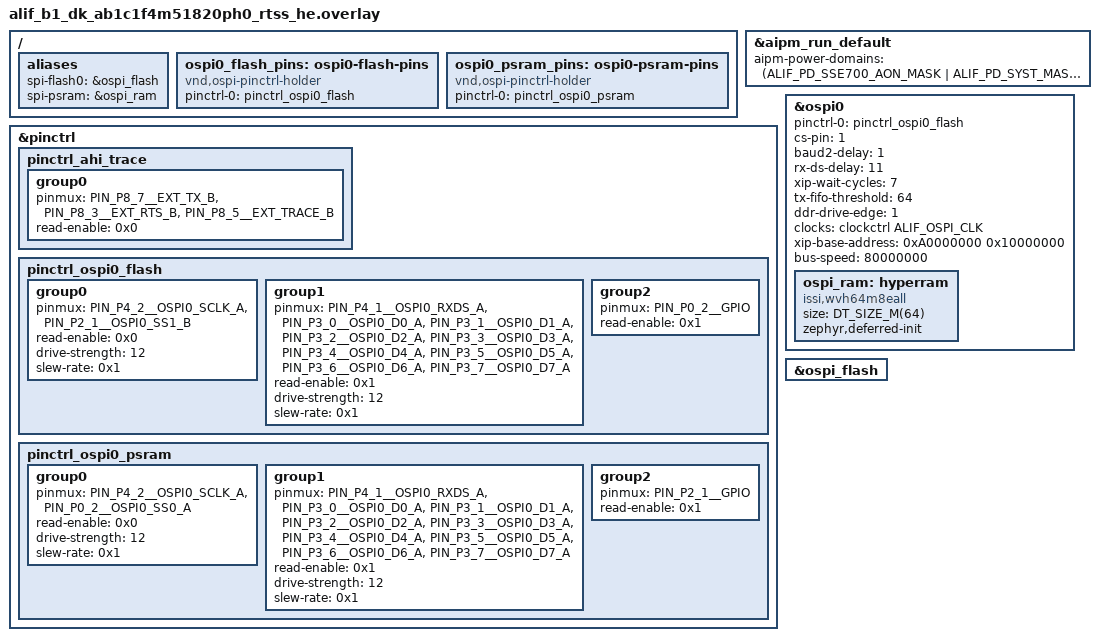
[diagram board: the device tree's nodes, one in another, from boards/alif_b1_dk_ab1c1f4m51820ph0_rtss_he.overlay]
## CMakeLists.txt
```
# SPDX-License-Identifier: Apache-2.0

cmake_minimum_required(VERSION 3.20.0)
find_package(Zephyr REQUIRED HINTS $ENV{ZEPHYR_BASE})
project(spi_flash)

target_sources(app PRIVATE src/main.c)
target_sources_ifdef(CONFIG_MEMC app PRIVATE src/flash_to_psram.c)
```

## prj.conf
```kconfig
# Copyright (C) 2026 Alif Semiconductor.
# SPDX-License-Identifier: Apache-2.0

#FLASH
CONFIG_STDOUT_CONSOLE=y
CONFIG_FLASH=y
CONFIG_LOG=y
CONFIG_EVENTS=y
CONFIG_MAIN_STACK_SIZE=8192
CONFIG_FLASH_LOG_LEVEL_DBG=n

# CRC32 used by flash_to_psram_verify()
CONFIG_CRC=y

# Bring-up diagnostics: flush prints synchronously and dump faults.
CONFIG_LOG_MODE_IMMEDIATE=y
CONFIG_EXCEPTION_STACK_TRACE=y

#RAM
CONFIG_PRINTK=y
CONFIG_ARM_MPU=y
CONFIG_MEMC=y
CONFIG_MEMC_OSPI_ALIF=y
CONFIG_USE_ALIF_HAL_OSPI=y
```

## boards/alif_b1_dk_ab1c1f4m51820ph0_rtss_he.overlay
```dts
/*
 * SPDX-FileCopyrightText: Copyright Alif Semiconductor
 * SPDX-License-Identifier: Apache-2.0
 */

#include <dt-bindings/misc/alif_aipm_common.h>

/* Keep the Debug Subsystem (DBSS) powered so a debugger stays connected. */
&aipm_run_default {
	aipm-power-domains = <(ALIF_PD_SSE700_AON_MASK |
			       ALIF_PD_SYST_MASK | ALIF_PD_SESS_MASK |
			       ALIF_PD_DBSS_MASK)>;
};

/*
 * Combined OSPI0 configuration: both the external OSPI flash (SS1_B / P2_1)
 * and the HyperRAM PSRAM (SS0_A / P0_2) share the single OSPI0 controller,
 * the SCLK, the D0..D7 data lines and the RXDS strobe.
 *
 * Build this WITHOUT the `ospi-flash` / `ospi-psram` snippets -- this overlay
 * already declares both devices and all pinctrl states.
 *
 * KEY: the two devices must NOT be muxed onto the bus at the same time. When
 * the PSRAM chip-select (SS0_A) is muxed while the flash performs an octal-DDR
 * read, the physically-present HyperRAM loads the shared RXDS strobe and the
 * read never completes (hang). The loader (flash_to_psram.c) therefore owns
 * two pinctrl states and swaps them every chunk so that exactly one device is
 * connected to the bus at a time; the deselected device's chip-select is
 * parked on GPIO (released) so it stays fully quiescent.
 *
 * The PSRAM (memc) driver is `zephyr,deferred-init`: it never runs. The loader
 * drives the OSPI0 HAL directly to alternate flash reads and PSRAM XiP writes.
 */

/ {
	aliases {
		spi-flash0 = &ospi_flash;
		spi-psram = &ospi_ram;
	};

	/*
	 * Helper nodes that let the loader apply either pin state at run time.
	 * They carry no `reg` (the Alif pinctrl driver ignores it) and a
	 * placeholder compatible (`vnd,ospi-pinctrl-holder`, no driver) so that
	 * gen_defines types `pinctrl-0` as phandles and PINCTRL_DT_DEFINE() in
	 * the loader can own a pinctrl_dev_config for each state. Keeping the
	 * custom "psram" state off &ospi0 avoids breaking the flash driver's
	 * PINCTRL_DT_DEFINE.
	 */
	ospi0_flash_pins: ospi0-flash-pins {
		compatible = "vnd,ospi-pinctrl-holder";
		pinctrl-0 = <&pinctrl_ospi0_flash>;
		pinctrl-names = "default";
	};

	ospi0_psram_pins: ospi0-psram-pins {
		compatible = "vnd,ospi-pinctrl-holder";
		pinctrl-0 = <&pinctrl_ospi0_psram>;
		pinctrl-names = "default";
	};
};

&pinctrl {
	/*
	 * The board default `pinctrl_ahi_trace` muxes the AHI-trace UART onto
	 * three OSPI0 pins (P4_2 = SCLK, P4_1 = RXDS, P3_6 = D6), which clobbers
	 * the flash bus at boot and hangs the first read. Re-route trace to the
	 * P8 pins (matches the vendor `ospi-flash` snippet) so OSPI0 keeps them.
	 */
	pinctrl_ahi_trace: pinctrl_ahi_trace {
		group0 {
			pinmux = <PIN_P8_7__EXT_TX_B>,
				 <PIN_P8_3__EXT_RTS_B>,
				 <PIN_P8_5__EXT_TRACE_B>;
			read-enable = <0x0>;
		};
	};

	/*
	 * FLASH bus state: SCLK + flash CS (SS1_B) driven, data/strobe as input,
	 * PSRAM CS (P0_2) parked on GPIO so the HyperRAM is released.
	 */
	pinctrl_ospi0_flash: pinctrl_ospi0_flash {
		group0 {
			pinmux = <PIN_P4_2__OSPI0_SCLK_A>,
				 <PIN_P2_1__OSPI0_SS1_B>;
			read-enable = <0x0>;
			drive-strength = <12>;
			slew-rate = <0x1>;
		};

		group1 {
			pinmux = <PIN_P4_1__OSPI0_RXDS_A>,
				 <PIN_P3_0__OSPI0_D0_A>,
				 <PIN_P3_1__OSPI0_D1_A>,
				 <PIN_P3_2__OSPI0_D2_A>,
				 <PIN_P3_3__OSPI0_D3_A>,
				 <PIN_P3_4__OSPI0_D4_A>,
				 <PIN_P3_5__OSPI0_D5_A>,
				 <PIN_P3_6__OSPI0_D6_A>,
				 <PIN_P3_7__OSPI0_D7_A>;
			read-enable = <0x1>;
			drive-strength = <12>;
			slew-rate = <0x1>;
		};

		group2 {
			/* Park PSRAM CS as GPIO input -> HyperRAM released. */
			pinmux = <PIN_P0_2__GPIO>;
			read-enable = <0x1>;
		};
	};

	/*
	 * PSRAM bus state: SCLK + PSRAM CS (SS0_A) driven, data/strobe as input,
	 * flash CS (P2_1) parked on GPIO so the flash is released.
	 */
	pinctrl_ospi0_psram: pinctrl_ospi0_psram {
		group0 {
			pinmux = <PIN_P4_2__OSPI0_SCLK_A>,
				 <PIN_P0_2__OSPI0_SS0_A>;
			read-enable = <0x0>;
			drive-strength = <12>;
			slew-rate = <0x1>;
		};

		group1 {
			pinmux = <PIN_P4_1__OSPI0_RXDS_A>,
				 <PIN_P3_0__OSPI0_D0_A>,
				 <PIN_P3_1__OSPI0_D1_A>,
				 <PIN_P3_2__OSPI0_D2_A>,
				 <PIN_P3_3__OSPI0_D3_A>,
				 <PIN_P3_4__OSPI0_D4_A>,
				 <PIN_P3_5__OSPI0_D5_A>,
				 <PIN_P3_6__OSPI0_D6_A>,
				 <PIN_P3_7__OSPI0_D7_A>;
			read-enable = <0x1>;
			drive-strength = <12>;
			slew-rate = <0x1>;
		};

		group2 {
			/* Park flash CS as GPIO input -> flash released. */
			pinmux = <PIN_P2_1__GPIO>;
			read-enable = <0x1>;
		};
	};
};

&ospi0 {
	/*
	 * Boot state = flash pins so the flash driver comes up cleanly. The
	 * loader re-applies this (or the PSRAM state) as it alternates.
	 *
	 * cs-pin = 1 -> flash uses SS1_B. Controller timing here is the flash
	 * known-good set (ddr-drive-edge=1, rx-ds-delay=11); the loader
	 * reprograms ddr-drive-edge/rx-ds-delay to the PSRAM values around each
	 * XiP write. xip-wait-cycles / xip-base-address are the PSRAM XiP set.
	 */
	pinctrl-0 = <&pinctrl_ospi0_flash>;
	pinctrl-names = "default";

	cs-pin = <1>;
	baud2-delay = <1>;
	rx-ds-delay = <11>;
	xip-wait-cycles = <7>;
	tx-fifo-threshold = <64>;
	ddr-drive-edge = <1>;
	clocks = <&clockctrl ALIF_OSPI_CLK>;
	xip-base-address = <0xA0000000 0x10000000>;
	bus-speed = <80000000>;
	status = "okay";

	ospi_ram: hyperram {
		compatible = "issi,wvh64m8eall";
		size = <DT_SIZE_M(64)>;
		/* Never brought up as a Zephyr device; the loader drives XiP. */
		zephyr,deferred-init;
		status = "okay";
	};
};

&ospi_flash {
	status = "okay";
};
```

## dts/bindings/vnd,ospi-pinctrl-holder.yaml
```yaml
# SPDX-FileCopyrightText: Copyright Alif Semiconductor
# SPDX-License-Identifier: Apache-2.0

# Placeholder node that only carries an OSPI0 pinctrl state so the loader can
# own a pinctrl_dev_config (via PINCTRL_DT_DEFINE) and apply the state at run
# time. Including pinctrl-device.yaml is what makes gen_defines type the
# `pinctrl-0` property as phandles (otherwise the pinctrl phandle/child macros
# are not emitted for the node).

description: OSPI pinctrl state holder (no driver, runtime pin switching only)

compatible: "vnd,ospi-pinctrl-holder"

include: [pinctrl-device.yaml]
```

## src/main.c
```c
/*
 * Copyright (c) 2024 Alif Semiconductor
 * SPDX-License-Identifier: Apache-2.0
 */

#include <stdio.h>
#include <string.h>
#include <zephyr/device.h>
#include <zephyr/devicetree.h>
#include <zephyr/drivers/flash.h>
#include <zephyr/kernel.h>

#include "flash_to_psram.h"

#define SPI_FLASH_TEST_REGION_OFFSET 0x0
#define SPI_FLASH_SECTOR_SIZE        4096
#define BUFF_SIZE                    1024

const struct flash_parameters *flash_param;

int main(void)
{
	const struct device *flash_dev = DEVICE_DT_GET(DT_ALIAS(spi_flash0));

	printk("main: start\n");

	if (!device_is_ready(flash_dev)) {
		printk("%s: device not ready.\n", flash_dev->name);
		return -1;
	}

	/*
	 * Copy the first 4MB of the flash into the PSRAM XiP window and verify
	 * it. The copy alternates OSPI0 between the flash and the PSRAM one chunk
	 * at a time and leaves the bus in PSRAM XiP mode -- return once done.
	 */
	int err = flash_to_psram_copy(0, 0, 4 * 1024 * 1024);

	if (err != 0) {
		printk("flash_to_psram_copy failed: %d\n", err);
		return err;
	}

	err = flash_to_psram_verify(0, 4 * 1024 * 1024);
	if (err != 0) {
		printk("flash_to_psram_verify failed: %d\n", err);
		return err;
	}

	return 0;
}
```

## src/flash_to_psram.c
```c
/*
 * SPDX-FileCopyrightText: Copyright Alif Semiconductor
 * SPDX-License-Identifier: Apache-2.0
 *
 * OSPI-flash -> OSPI-HyperRAM (PSRAM) copy loader for the Balletto B1
 * (alif_b1_dk .../rtss_he).
 *
 * The OSPI flash and the HyperRAM PSRAM share the single OSPI0 controller
 * (SCLK, D0..D7 and the RXDS strobe). They cannot both be connected to the
 * bus at once, so this loader copies an arbitrarily large payload by
 * *alternating* the bus between the two devices, one SRAM-sized chunk at a
 * time -- there is no requirement that the payload fit in SRAM.
 *
 * Per chunk:
 *
 *   FLASH phase:
 *     - leave PSRAM XiP mode                        (aes_disable_xip)
 *     - apply the flash pin state                   (flash CS muxed,
 *                                                    PSRAM CS parked on GPIO)
 *     - restore flash DDR-capture timing            (ddr-drive-edge / rx-ds)
 *     - flash_read() one chunk into an SRAM buffer  (Zephyr flash driver,
 *                                                    IRQ-backed, owns OSPI0
 *                                                    command mode)
 *   PSRAM phase:
 *     - apply the PSRAM pin state                   (PSRAM CS muxed,
 *                                                    flash CS parked on GPIO)
 *     - set PSRAM DDR-capture timing                (ddr-drive-edge / rx-ds)
 *     - reconfigure OSPI0 for octal-DDR HyperRAM    (prepare_transfer +
 *                                                    ospi_hyperbus_xip_init +
 *                                                    aes_enable_xip)
 *     - copy the chunk into the PSRAM XiP window    (memory-mapped stores)
 *
 * Because the *deselected* device's chip-select is parked on GPIO, only one
 * device is ever electrically connected to the shared RXDS strobe, which is
 * what makes the octal-DDR flash read reliable (a muxed idle HyperRAM CS
 * otherwise loads the strobe and the read hangs).
 *
 * The PSRAM XiP window (0xA0000000) is in the Cortex-M55 default Device
 * memory region (non-cacheable, ordered), so the memory-mapped writes reach
 * the controller directly; a single completion barrier per chunk is enough.
 *
 * On return from a successful copy the bus is left in PSRAM XiP mode with the
 * PSRAM pins applied, so the copied data is immediately readable (execute-in-
 * place) at PSRAM_XIP_BASE and flash_to_psram_verify() can read it back.
 *
 * NOTE: board bring-up code. The per-device DDR-capture timing values below
 * are the vendor snippet defaults and can be tuned on real hardware.
 */

#include <zephyr/kernel.h>
#include <zephyr/device.h>
#include <zephyr/devicetree.h>
#include <zephyr/drivers/flash.h>
#include <zephyr/drivers/pinctrl.h>
#include <zephyr/sys/util.h>
#include <zephyr/sys/barrier.h>
#include <zephyr/sys/crc.h>
#include <string.h>

#include "flash_to_psram.h"

#define FLASH_NODE	DT_ALIAS(spi_flash0)
#define PSRAM_NODE	DT_ALIAS(spi_psram)

#if DT_NODE_EXISTS(FLASH_NODE) && DT_NODE_EXISTS(PSRAM_NODE)

#include "ospi_hal.h"
#include "ospi.h"

/* The OSPI0 controller node (parent of both the flash and the PSRAM child). */
#define OSPI0_NODE	DT_PARENT(PSRAM_NODE)

/* PSRAM XiP window base address (declared on the OSPI0 controller node). */
#define PSRAM_XIP_BASE	DT_PROP_BY_IDX(OSPI0_NODE, xip_base_address, 0)

/*
 * Per-device DDR-capture timing. Flash values are the OSPI0 node defaults;
 * PSRAM values are the vendor `ospi-psram` snippet defaults. They are applied
 * to the shared controller registers around each phase. Override from the
 * build if a board needs different values.
 */
#ifndef FLASH_DDR_DRIVE_EDGE
#define FLASH_DDR_DRIVE_EDGE	1U
#endif
#ifndef FLASH_RX_DS_DELAY
#define FLASH_RX_DS_DELAY	11U
#endif
#ifndef PSRAM_DDR_DRIVE_EDGE
#define PSRAM_DDR_DRIVE_EDGE	0U
#endif
#ifndef PSRAM_RX_DS_DELAY
#define PSRAM_RX_DS_DELAY	8U
#endif

/* PSRAM chip-select (SS0_A). */
#define PSRAM_CS_PIN		0U

/* HyperRAM R/W transactions are octal-DDR commands with 16-bit frames. */
#define PSRAM_OSPI_DFS		16U

/* SRAM staging buffer size per alternating chunk (tunable). */
#ifndef FLASH_TO_PSRAM_CHUNK
#define FLASH_TO_PSRAM_CHUNK	(8U * 1024U)
#endif

/* Pin states (owned via helper DT nodes so the flash driver is unaffected). */
PINCTRL_DT_DEFINE(DT_NODELABEL(ospi0_flash_pins));
PINCTRL_DT_DEFINE(DT_NODELABEL(ospi0_psram_pins));

static const struct pinctrl_dev_config *const flash_pins =
	PINCTRL_DT_DEV_CONFIG_GET(DT_NODELABEL(ospi0_flash_pins));
static const struct pinctrl_dev_config *const psram_pins =
	PINCTRL_DT_DEV_CONFIG_GET(DT_NODELABEL(ospi0_psram_pins));

static struct ospi_regs *const ospi_regs =
	(struct ospi_regs *)DT_REG_ADDR(OSPI0_NODE);
static struct ospi_aes_regs *const ospi_aes =
	(struct ospi_aes_regs *)DT_PROP_BY_IDX(OSPI0_NODE, aes_reg, 0);

static uint8_t stage_buf[FLASH_TO_PSRAM_CHUNK] __aligned(4);

static HAL_OSPI_Handle_T psram_handle;
static bool psram_handle_ready;

static void loader_ospi_event_cb(uint32_t event, void *user_data)
{
	ARG_UNUSED(event);
	ARG_UNUSED(user_data);
}

/*
 * One-time: grab a second OSPI0 HAL instance for the PSRAM chip-select. This
 * writes the shared controller globals (thresholds, bus speed, baud2); the
 * per-phase timing (ddr-drive-edge / rx-ds-delay) is (re)programmed on every
 * switch, so the values passed here only seed the instance.
 */
static int psram_handle_init(void)
{
	struct ospi_init init_config;
	int32_t ret;

	if (psram_handle_ready) {
		return 0;
	}

	memset(&init_config, 0, sizeof(init_config));
	init_config.core_clk = DT_PROP(OSPI0_NODE, clock_frequency);
	init_config.bus_speed = DT_PROP(OSPI0_NODE, bus_speed);
	init_config.tx_fifo_threshold = DT_PROP(OSPI0_NODE, tx_fifo_threshold);
	init_config.rx_fifo_threshold = 0U;
	init_config.rx_sample_delay = 0U;
	init_config.ddr_drive_edge = PSRAM_DDR_DRIVE_EDGE;
	init_config.cs_pin = PSRAM_CS_PIN;
	init_config.rx_ds_delay = PSRAM_RX_DS_DELAY;
	init_config.baud2_delay = DT_PROP(OSPI0_NODE, baud2_delay);
	init_config.base_regs = (uint32_t *)ospi_regs;
	init_config.aes_regs = (uint32_t *)ospi_aes;
	init_config.event_cb = loader_ospi_event_cb;
	init_config.user_data = NULL;

	ret = alif_hal_ospi_initialize(&psram_handle, &init_config);
	if (ret != 0) {
		printk("copy: psram HAL init failed: %d\n", (int)ret);
		return -EIO;
	}

	psram_handle_ready = true;
	return 0;
}

/* Hand the shared bus to the flash: leave XiP, mux flash pins, flash timing. */
static void bus_to_flash(void)
{
	aes_disable_xip(ospi_aes);
	(void)pinctrl_apply_state(flash_pins, PINCTRL_STATE_DEFAULT);
	ospi_set_ddr_drive_edge(ospi_regs, FLASH_DDR_DRIVE_EDGE);
	ospi_aes->AES_RXDS_DLY = FLASH_RX_DS_DELAY;
}

/*
 * Hand the shared bus to the PSRAM: mux PSRAM pins, PSRAM timing, reconfigure
 * OSPI0 for octal-DDR HyperRAM and enter memory-mapped XiP.
 */
static void bus_to_psram(void)
{
	struct ospi_trans_config trans_conf;
	struct ospi_xip_config xip_cfg;

	(void)pinctrl_apply_state(psram_pins, PINCTRL_STATE_DEFAULT);
	ospi_set_ddr_drive_edge(ospi_regs, PSRAM_DDR_DRIVE_EDGE);
	ospi_aes->AES_RXDS_DLY = PSRAM_RX_DS_DELAY;

	memset(&trans_conf, 0, sizeof(trans_conf));
	trans_conf.frame_size = PSRAM_OSPI_DFS;
	trans_conf.frame_format = OSPI_FRF_OCTAL;
	trans_conf.ddr_enable = OSPI_DDR_ENABLE;
	(void)alif_hal_ospi_prepare_transfer(psram_handle, &trans_conf);

	memset(&xip_cfg, 0, sizeof(xip_cfg));
	xip_cfg.xip_wait_cycles = DT_PROP(OSPI0_NODE, xip_wait_cycles);
	xip_cfg.xip_cs_pin = PSRAM_CS_PIN;
	ospi_hyperbus_xip_init(ospi_regs, &xip_cfg);

	aes_enable_xip(ospi_aes);
}

/* Copy one chunk from the SRAM buffer into the PSRAM XiP window (16-bit). */
static void psram_xip_write(off_t psram_off, const uint8_t *src, size_t len)
{
	volatile uint16_t *dst =
		(volatile uint16_t *)(uintptr_t)(PSRAM_XIP_BASE + psram_off);
	const uint16_t *words = (const uint16_t *)src;
	size_t nwords = len / sizeof(uint16_t);

	for (size_t i = 0; i < nwords; i++) {
		dst[i] = words[i];
	}

	barrier_dsync_fence_full();
}

int flash_to_psram_copy(off_t flash_off, off_t psram_off, size_t len)
{
	const struct device *flash_dev = DEVICE_DT_GET(FLASH_NODE);
	int ret;

	if (len == 0U) {
		return 0;
	}

	/* 16-bit HyperRAM frames: offsets and length must be 2-byte aligned. */
	if ((len % 2U) != 0U || (psram_off % 2) != 0) {
		return -EINVAL;
	}

	if (!device_is_ready(flash_dev)) {
		return -ENODEV;
	}

	ret = psram_handle_init();
	if (ret != 0) {
		return ret;
	}

	printk("copy: %zu bytes flash@0x%lx -> psram@0x%lx (chunk %uB)\n",
	       len, (unsigned long)flash_off, (unsigned long)psram_off,
	       (unsigned int)FLASH_TO_PSRAM_CHUNK);

	for (size_t done = 0; done < len; done += FLASH_TO_PSRAM_CHUNK) {
		size_t chunk = MIN((size_t)FLASH_TO_PSRAM_CHUNK, len - done);

		/* FLASH phase: stage one chunk from flash into SRAM. */
		bus_to_flash();
		ret = flash_read(flash_dev, flash_off + done, stage_buf, chunk);
		if (ret != 0) {
			printk("copy: flash_read @0x%zx failed: %d\n",
			       (size_t)flash_off + done, ret);
			return ret;
		}

		/* PSRAM phase: push the chunk into the PSRAM XiP window. */
		bus_to_psram();
		psram_xip_write(psram_off + done, stage_buf, chunk);
	}

	printk("copy: done (%zu bytes, bus left in PSRAM XiP mode)\n", len);
	return 0;
}

/* Layout produced by test_4mb.bin: 8-byte magic, offset-encoded words, CRC32 tail. */
#define TEST_MAGIC		"ALIFPSRM"
#define TEST_MAGIC_LEN		8U

int flash_to_psram_verify(off_t psram_off, size_t len)
{
	const uint8_t *base = (const uint8_t *)(uintptr_t)(PSRAM_XIP_BASE + psram_off);
	uint32_t calc_crc, trailer;
	bool magic_ok, pattern_ok, crc_ok;

	if (len < (TEST_MAGIC_LEN + 4U) || (len % 4U) != 0U) {
		return -EINVAL;
	}

	/* 1. Magic header copied intact. */
	magic_ok = (memcmp(base, TEST_MAGIC, TEST_MAGIC_LEN) == 0);
	if (magic_ok) {
		printk("verify: magic OK (%.8s)\n", base);
	} else {
		printk("verify: magic FAIL (got %02x %02x %02x %02x ...)\n",
		       base[0], base[1], base[2], base[3]);
	}

	/* 2. Every word (past the magic, before the CRC tail) equals its offset. */
	pattern_ok = true;
	for (size_t off = TEST_MAGIC_LEN; off < (len - 4U); off += 4U) {
		uint32_t word;

		memcpy(&word, base + off, sizeof(word));
		if (word != (uint32_t)off) {
			printk("verify: pattern FAIL @0x%05zx exp 0x%08x got 0x%08x\n",
			       off, (uint32_t)off, word);
			pattern_ok = false;
			break;
		}
	}
	if (pattern_ok) {
		printk("verify: offset-word pattern OK (0x%x..0x%x)\n",
		       (uint32_t)TEST_MAGIC_LEN, (uint32_t)(len - 8U));
	}

	/* 3. CRC32 over everything but the 4-byte trailer. */
	calc_crc = crc32_ieee(base, len - 4U);
	memcpy(&trailer, base + (len - 4U), sizeof(trailer));
	crc_ok = (calc_crc == trailer);
	printk("verify: crc32 %s (calc 0x%08x, stored 0x%08x)\n",
	       crc_ok ? "OK" : "FAIL", calc_crc, trailer);

	if (magic_ok && pattern_ok && crc_ok) {
		printk("verify: PASS -- %zu bytes copied to PSRAM XiP @0x%08lx\n",
		       len, (unsigned long)(uintptr_t)base);
		return 0;
	}

	printk("verify: FAIL\n");
	return -EIO;
}

#else /* !(flash0 && psram aliases) */

int flash_to_psram_copy(off_t flash_off, off_t psram_off, size_t len)
{
	ARG_UNUSED(flash_off);
	ARG_UNUSED(psram_off);
	ARG_UNUSED(len);

	return -ENOTSUP;
}

int flash_to_psram_verify(off_t psram_off, size_t len)
{
	ARG_UNUSED(psram_off);
	ARG_UNUSED(len);

	return -ENOTSUP;
}

#endif /* flash0 && psram aliases */
```

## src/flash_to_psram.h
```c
/*
 * SPDX-FileCopyrightText: Copyright Alif Semiconductor
 * SPDX-License-Identifier: Apache-2.0
 */

#ifndef FLASH_TO_PSRAM_H_
#define FLASH_TO_PSRAM_H_

#include <sys/types.h>
#include <stddef.h>

/**
 * @brief Copy a payload from OSPI flash into OSPI HyperRAM (PSRAM) XiP.
 *
 * Copies @p len bytes starting at @p flash_off in the OSPI flash to the PSRAM
 * XiP window at @p psram_off. Flash and PSRAM share one OSPI0 controller, so
 * the copy alternates the bus between them one SRAM-sized chunk at a time --
 * the payload may be arbitrarily large (it need not fit in SRAM).
 *
 * On success the bus is left in PSRAM XiP mode, so the copied data is
 * immediately readable at the PSRAM XiP base address.
 *
 * @param flash_off  Source byte offset within the OSPI flash.
 * @param psram_off  Destination byte offset within the PSRAM XiP window
 *                   (must be 2-byte aligned).
 * @param len        Number of bytes to copy (must be a multiple of 2).
 *
 * @retval 0        on success.
 * @retval -EINVAL  if @p len or @p psram_off is not 2-byte aligned.
 * @retval -ENODEV  if the flash device is not ready.
 * @retval -EIO     if the PSRAM OSPI HAL instance could not be initialised.
 * @retval <0       propagated flash_read() error.
 * @retval -ENOTSUP if the flash/psram aliases are not present.
 */
int flash_to_psram_copy(off_t flash_off, off_t psram_off, size_t len);

/**
 * @brief Verify a payload previously copied into the PSRAM XiP window.
 *
 * Reads back @p len bytes from the PSRAM XiP window at @p psram_off and
 * checks the test.bin layout: 8-byte "ALIFPSRM" magic, offset-encoded 32-bit
 * words, and a trailing little-endian CRC32 over the first (len - 4) bytes.
 * Progress and pass/fail are printed via printk.
 *
 * @param psram_off  Byte offset within the PSRAM XiP window.
 * @param len        Number of bytes to verify (multiple of 4, >= 12).
 *
 * @retval 0        on success (all checks passed).
 * @retval -EINVAL  if @p len is too small or not word-aligned.
 * @retval -EIO     if any check failed.
 * @retval -ENOTSUP if the flash/psram aliases are not present.
 */
int flash_to_psram_verify(off_t psram_off, size_t len);

#endif /* FLASH_TO_PSRAM_H_ */
```
